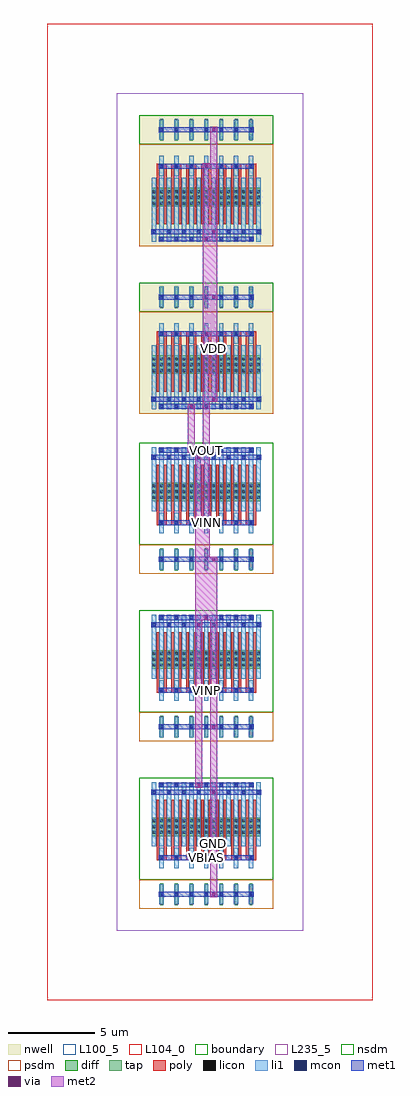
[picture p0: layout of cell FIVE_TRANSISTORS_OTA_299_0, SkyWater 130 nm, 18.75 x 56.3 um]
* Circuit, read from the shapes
.subckt FIVE_TRANSISTORS_OTA_299_0 GND VBIAS VDD VINN VINP VOUT
XM1 n1 VBIAS GND GND sky130_fd_pr__nfet_01v8 w=1.05 l=0.15 m=14
XM2 n2 VINP n1 GND sky130_fd_pr__nfet_01v8 w=1.05 l=0.15 m=14
XM3 VOUT VINN n1 GND sky130_fd_pr__nfet_01v8 w=1.05 l=0.15 m=14
XM4 VOUT n2 VDD VDD sky130_fd_pr__pfet_01v8 w=1.05 l=0.15 m=14
XM5 n2 n2 VDD VDD sky130_fd_pr__pfet_01v8 w=1.05 l=0.15 m=14
.ends

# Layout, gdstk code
import gdstk
lib = gdstk.Library(unit=1e-6, precision=1e-09)
def R(c, l, rs):  # rectangles x0, y0, x1, y1
    for r in rs: c.add(gdstk.rectangle(r[:2], r[2:], *l))
def A(c, l, x, y, w, h, nx, ny, dx, dy):  # array of equal rectangles
    R(c, l, [(x+i*dx, y+j*dy, x+i*dx+w, y+j*dy+h) for i in range(nx) for j in range(ny)])
def P(c, l, *ps):  # polygons
    for p in ps: c.add(gdstk.Polygon(p, *l))
nwell = (64, 20)
diff = (65, 20)
tap = (65, 44)
poly = (66, 20)
licon = (66, 44)
li1 = (67, 20)
mcon = (67, 44)
met1 = (68, 20)
via = (68, 44)
met2 = (69, 20)
nsdm = (93, 44)
psdm = (94, 20)
L100_5 = (100, 5)
L104_0 = (104, 0)
boundary = (235, 4)
L235_5 = (235, 5)

dcl_pmos_s_35191781_x7_y = lib.new_cell('DCL_PMOS_S_35191781_X7_Y1_1746762818')
R(dcl_pmos_s_35191781_x7_y, nwell, [(1.29,0.84,9.03,8.4)])
R(dcl_pmos_s_35191781_x7_y, diff, [(2.025,3.15,8.295,4.2)])
A(dcl_pmos_s_35191781_x7_y, tap, 2.495, 6.915, 0.17, 1.29, 7, 1, 0.86, 0)
A(dcl_pmos_s_35191781_x7_y, poly, 2.29, 2.1, 0.15, 3.36, 14, 1, 0.43, 0)
A(dcl_pmos_s_35191781_x7_y, poly, 2.29, 5.325, 0.58, 0.27, 7, 1, 0.86, 0)
A(dcl_pmos_s_35191781_x7_y, licon, 2.065, 3.23, 0.17, 0.17, 3, 3, 0.43, 0.34)
A(dcl_pmos_s_35191781_x7_y, licon, 2.925, 3.23, 0.17, 0.17, 3, 3, 0.43, 0.34)
A(dcl_pmos_s_35191781_x7_y, licon, 3.785, 3.23, 0.17, 0.17, 3, 3, 0.43, 0.34)
A(dcl_pmos_s_35191781_x7_y, licon, 4.645, 3.23, 0.17, 0.17, 3, 3, 0.43, 0.34)
A(dcl_pmos_s_35191781_x7_y, licon, 5.505, 3.23, 0.17, 0.17, 3, 3, 0.43, 0.34)
A(dcl_pmos_s_35191781_x7_y, licon, 6.365, 3.23, 0.17, 0.17, 3, 3, 0.43, 0.34)
A(dcl_pmos_s_35191781_x7_y, licon, 7.225, 3.23, 0.17, 0.17, 3, 3, 0.43, 0.34)
A(dcl_pmos_s_35191781_x7_y, licon, 2.495, 5.375, 0.17, 0.17, 7, 2, 0.86, 2.1)
A(dcl_pmos_s_35191781_x7_y, li1, 2.025, 1.09, 0.25, 3.7, 15, 1, 0.43, 0)
A(dcl_pmos_s_35191781_x7_y, li1, 2.455, 4.87, 0.25, 1.18, 7, 2, 0.86, 2.1)
A(dcl_pmos_s_35191781_x7_y, mcon, 2.495, 1.175, 0.17, 0.17, 7, 2, 0.86, 4.2)
A(dcl_pmos_s_35191781_x7_y, mcon, 2.065, 1.595, 0.17, 0.17, 8, 1, 0.86, 0)
A(dcl_pmos_s_35191781_x7_y, mcon, 2.495, 7.475, 0.17, 0.17, 7, 1, 0.86, 0)
R(dcl_pmos_s_35191781_x7_y, met1, [(2.41,1.12,7.91,1.4), (1.98,1.54,8.34,1.82), (2.41,5.32,7.91,5.6), (2.41,7.42,7.91,7.7)])
R(dcl_pmos_s_35191781_x7_y, via, [(5.085,1.185,5.235,1.335), (5.515,1.605,5.665,1.755), (5.085,5.385,5.235,5.535), (5.515,7.485,5.665,7.635)])
R(dcl_pmos_s_35191781_x7_y, met2, [(4.96,1.1,5.36,5.62), (5.39,1.52,5.79,7.72)])
R(dcl_pmos_s_35191781_x7_y, nsdm, [(1.29,6.72,9.03,8.4)])
R(dcl_pmos_s_35191781_x7_y, psdm, [(1.29,0.84,9.03,6.72)])
R(dcl_pmos_s_35191781_x7_y, L100_5, [(0,0,10.75,9.66)])
R(dcl_pmos_s_35191781_x7_y, boundary, [(0,0,10.75,9.66)])

nmos_s_30358784_x7_y1_17 = lib.new_cell('NMOS_S_30358784_X7_Y1_1746762821')
R(nmos_s_30358784_x7_y1_17, diff, [(2.025,3.15,8.295,4.2)])
A(nmos_s_30358784_x7_y1_17, tap, 2.495, 6.915, 0.17, 1.29, 7, 1, 0.86, 0)
A(nmos_s_30358784_x7_y1_17, poly, 2.29, 2.1, 0.15, 3.36, 14, 1, 0.43, 0)
A(nmos_s_30358784_x7_y1_17, poly, 2.29, 5.325, 0.58, 0.27, 7, 1, 0.86, 0)
A(nmos_s_30358784_x7_y1_17, licon, 2.065, 3.23, 0.17, 0.17, 3, 3, 0.43, 0.34)
A(nmos_s_30358784_x7_y1_17, licon, 2.925, 3.23, 0.17, 0.17, 3, 3, 0.43, 0.34)
A(nmos_s_30358784_x7_y1_17, licon, 3.785, 3.23, 0.17, 0.17, 3, 3, 0.43, 0.34)
A(nmos_s_30358784_x7_y1_17, licon, 4.645, 3.23, 0.17, 0.17, 3, 3, 0.43, 0.34)
A(nmos_s_30358784_x7_y1_17, licon, 5.505, 3.23, 0.17, 0.17, 3, 3, 0.43, 0.34)
A(nmos_s_30358784_x7_y1_17, licon, 6.365, 3.23, 0.17, 0.17, 3, 3, 0.43, 0.34)
A(nmos_s_30358784_x7_y1_17, licon, 7.225, 3.23, 0.17, 0.17, 3, 3, 0.43, 0.34)
A(nmos_s_30358784_x7_y1_17, licon, 2.495, 5.375, 0.17, 0.17, 7, 2, 0.86, 2.1)
A(nmos_s_30358784_x7_y1_17, li1, 2.025, 1.09, 0.25, 3.7, 15, 1, 0.43, 0)
A(nmos_s_30358784_x7_y1_17, li1, 2.455, 4.87, 0.25, 1.18, 7, 2, 0.86, 2.1)
A(nmos_s_30358784_x7_y1_17, mcon, 2.495, 1.175, 0.17, 0.17, 7, 2, 0.86, 4.2)
A(nmos_s_30358784_x7_y1_17, mcon, 2.065, 1.595, 0.17, 0.17, 8, 1, 0.86, 0)
A(nmos_s_30358784_x7_y1_17, mcon, 2.495, 7.475, 0.17, 0.17, 7, 1, 0.86, 0)
R(nmos_s_30358784_x7_y1_17, met1, [(2.41,1.12,7.91,1.4), (1.98,1.54,8.34,1.82), (2.41,5.32,7.91,5.6), (2.41,7.42,7.91,7.7)])
R(nmos_s_30358784_x7_y1_17, via, [(5.515,1.605,5.665,1.755), (5.515,7.485,5.665,7.635)])
R(nmos_s_30358784_x7_y1_17, met2, [(5.39,1.52,5.79,7.72)])
R(nmos_s_30358784_x7_y1_17, nsdm, [(1.29,0.84,9.03,6.72)])
R(nmos_s_30358784_x7_y1_17, psdm, [(1.29,6.72,9.03,8.4)])
R(nmos_s_30358784_x7_y1_17, L100_5, [(0,0,10.75,9.66)])
R(nmos_s_30358784_x7_y1_17, boundary, [(0,0,10.75,9.66)])

pmos_s_25226034_x7_y1_17 = lib.new_cell('PMOS_S_25226034_X7_Y1_1746762822')
R(pmos_s_25226034_x7_y1_17, nwell, [(1.29,0.84,9.03,8.4)])
R(pmos_s_25226034_x7_y1_17, diff, [(2.025,3.15,8.295,4.2)])
A(pmos_s_25226034_x7_y1_17, tap, 2.495, 6.915, 0.17, 1.29, 7, 1, 0.86, 0)
A(pmos_s_25226034_x7_y1_17, poly, 2.29, 2.1, 0.15, 3.36, 14, 1, 0.43, 0)
A(pmos_s_25226034_x7_y1_17, poly, 2.29, 5.325, 0.58, 0.27, 7, 1, 0.86, 0)
A(pmos_s_25226034_x7_y1_17, licon, 2.065, 3.23, 0.17, 0.17, 3, 3, 0.43, 0.34)
A(pmos_s_25226034_x7_y1_17, licon, 2.925, 3.23, 0.17, 0.17, 3, 3, 0.43, 0.34)
A(pmos_s_25226034_x7_y1_17, licon, 3.785, 3.23, 0.17, 0.17, 3, 3, 0.43, 0.34)
A(pmos_s_25226034_x7_y1_17, licon, 4.645, 3.23, 0.17, 0.17, 3, 3, 0.43, 0.34)
A(pmos_s_25226034_x7_y1_17, licon, 5.505, 3.23, 0.17, 0.17, 3, 3, 0.43, 0.34)
A(pmos_s_25226034_x7_y1_17, licon, 6.365, 3.23, 0.17, 0.17, 3, 3, 0.43, 0.34)
A(pmos_s_25226034_x7_y1_17, licon, 7.225, 3.23, 0.17, 0.17, 3, 3, 0.43, 0.34)
A(pmos_s_25226034_x7_y1_17, licon, 2.495, 5.375, 0.17, 0.17, 7, 2, 0.86, 2.1)
A(pmos_s_25226034_x7_y1_17, li1, 2.025, 1.09, 0.25, 3.7, 15, 1, 0.43, 0)
A(pmos_s_25226034_x7_y1_17, li1, 2.455, 4.87, 0.25, 1.18, 7, 2, 0.86, 2.1)
A(pmos_s_25226034_x7_y1_17, mcon, 2.495, 1.175, 0.17, 0.17, 7, 2, 0.86, 4.2)
A(pmos_s_25226034_x7_y1_17, mcon, 2.065, 1.595, 0.17, 0.17, 8, 1, 0.86, 0)
A(pmos_s_25226034_x7_y1_17, mcon, 2.495, 7.475, 0.17, 0.17, 7, 1, 0.86, 0)
R(pmos_s_25226034_x7_y1_17, met1, [(2.41,1.12,7.91,1.4), (1.98,1.54,8.34,1.82), (2.41,5.32,7.91,5.6), (2.41,7.42,7.91,7.7)])
R(pmos_s_25226034_x7_y1_17, via, [(5.515,1.605,5.665,1.755), (5.515,7.485,5.665,7.635)])
R(pmos_s_25226034_x7_y1_17, met2, [(5.39,1.52,5.79,7.72)])
R(pmos_s_25226034_x7_y1_17, nsdm, [(1.29,6.72,9.03,8.4)])
R(pmos_s_25226034_x7_y1_17, psdm, [(1.29,0.84,9.03,6.72)])
R(pmos_s_25226034_x7_y1_17, L100_5, [(0,0,10.75,9.66)])
R(pmos_s_25226034_x7_y1_17, boundary, [(0,0,10.75,9.66)])

nmos_4t_51745689_x7_y1_1 = lib.new_cell('NMOS_4T_51745689_X7_Y1_1746762819')
R(nmos_4t_51745689_x7_y1_1, diff, [(2.025,3.15,8.295,4.2)])
A(nmos_4t_51745689_x7_y1_1, tap, 2.495, 6.915, 0.17, 1.29, 7, 1, 0.86, 0)
A(nmos_4t_51745689_x7_y1_1, poly, 2.29, 2.1, 0.15, 3.36, 14, 1, 0.43, 0)
A(nmos_4t_51745689_x7_y1_1, poly, 2.29, 5.325, 0.58, 0.27, 7, 1, 0.86, 0)
A(nmos_4t_51745689_x7_y1_1, licon, 2.065, 3.23, 0.17, 0.17, 3, 3, 0.43, 0.34)
A(nmos_4t_51745689_x7_y1_1, licon, 2.925, 3.23, 0.17, 0.17, 3, 3, 0.43, 0.34)
A(nmos_4t_51745689_x7_y1_1, licon, 3.785, 3.23, 0.17, 0.17, 3, 3, 0.43, 0.34)
A(nmos_4t_51745689_x7_y1_1, licon, 4.645, 3.23, 0.17, 0.17, 3, 3, 0.43, 0.34)
A(nmos_4t_51745689_x7_y1_1, licon, 5.505, 3.23, 0.17, 0.17, 3, 3, 0.43, 0.34)
A(nmos_4t_51745689_x7_y1_1, licon, 6.365, 3.23, 0.17, 0.17, 3, 3, 0.43, 0.34)
A(nmos_4t_51745689_x7_y1_1, licon, 7.225, 3.23, 0.17, 0.17, 3, 3, 0.43, 0.34)
A(nmos_4t_51745689_x7_y1_1, licon, 2.495, 5.375, 0.17, 0.17, 7, 2, 0.86, 2.1)
A(nmos_4t_51745689_x7_y1_1, li1, 2.025, 1.09, 0.25, 3.7, 15, 1, 0.43, 0)
A(nmos_4t_51745689_x7_y1_1, li1, 2.455, 4.87, 0.25, 1.18, 7, 2, 0.86, 2.1)
A(nmos_4t_51745689_x7_y1_1, mcon, 2.495, 1.175, 0.17, 0.17, 7, 2, 0.86, 4.2)
A(nmos_4t_51745689_x7_y1_1, mcon, 2.065, 1.595, 0.17, 0.17, 8, 1, 0.86, 0)
A(nmos_4t_51745689_x7_y1_1, mcon, 2.495, 7.475, 0.17, 0.17, 7, 1, 0.86, 0)
R(nmos_4t_51745689_x7_y1_1, met1, [(2.41,1.12,7.91,1.4), (1.98,1.54,8.34,1.82), (2.41,5.32,7.91,5.6), (2.41,7.42,7.91,7.7)])
R(nmos_4t_51745689_x7_y1_1, nsdm, [(1.29,0.84,9.03,6.72)])
R(nmos_4t_51745689_x7_y1_1, psdm, [(1.29,6.72,9.03,8.4)])
R(nmos_4t_51745689_x7_y1_1, L100_5, [(0,0,10.75,9.66)])
R(nmos_4t_51745689_x7_y1_1, boundary, [(0,0,10.75,9.66)])

nmos_4t_82587761_x7_y1_1 = lib.new_cell('NMOS_4T_82587761_X7_Y1_1746762820')
R(nmos_4t_82587761_x7_y1_1, diff, [(2.025,3.15,8.295,4.2)])
A(nmos_4t_82587761_x7_y1_1, tap, 2.495, 6.915, 0.17, 1.29, 7, 1, 0.86, 0)
A(nmos_4t_82587761_x7_y1_1, poly, 2.29, 2.1, 0.15, 3.36, 14, 1, 0.43, 0)
A(nmos_4t_82587761_x7_y1_1, poly, 2.29, 5.325, 0.58, 0.27, 7, 1, 0.86, 0)
A(nmos_4t_82587761_x7_y1_1, licon, 2.065, 3.23, 0.17, 0.17, 3, 3, 0.43, 0.34)
A(nmos_4t_82587761_x7_y1_1, licon, 2.925, 3.23, 0.17, 0.17, 3, 3, 0.43, 0.34)
A(nmos_4t_82587761_x7_y1_1, licon, 3.785, 3.23, 0.17, 0.17, 3, 3, 0.43, 0.34)
A(nmos_4t_82587761_x7_y1_1, licon, 4.645, 3.23, 0.17, 0.17, 3, 3, 0.43, 0.34)
A(nmos_4t_82587761_x7_y1_1, licon, 5.505, 3.23, 0.17, 0.17, 3, 3, 0.43, 0.34)
A(nmos_4t_82587761_x7_y1_1, licon, 6.365, 3.23, 0.17, 0.17, 3, 3, 0.43, 0.34)
A(nmos_4t_82587761_x7_y1_1, licon, 7.225, 3.23, 0.17, 0.17, 3, 3, 0.43, 0.34)
A(nmos_4t_82587761_x7_y1_1, licon, 2.495, 5.375, 0.17, 0.17, 7, 2, 0.86, 2.1)
A(nmos_4t_82587761_x7_y1_1, li1, 2.025, 1.09, 0.25, 3.7, 15, 1, 0.43, 0)
A(nmos_4t_82587761_x7_y1_1, li1, 2.455, 4.87, 0.25, 1.18, 7, 2, 0.86, 2.1)
A(nmos_4t_82587761_x7_y1_1, mcon, 2.495, 1.175, 0.17, 0.17, 7, 2, 0.86, 4.2)
A(nmos_4t_82587761_x7_y1_1, mcon, 2.065, 1.595, 0.17, 0.17, 8, 1, 0.86, 0)
A(nmos_4t_82587761_x7_y1_1, mcon, 2.495, 7.475, 0.17, 0.17, 7, 1, 0.86, 0)
R(nmos_4t_82587761_x7_y1_1, met1, [(2.41,1.12,7.91,1.4), (1.98,1.54,8.34,1.82), (2.41,5.32,7.91,5.6), (2.41,7.42,7.91,7.7)])
R(nmos_4t_82587761_x7_y1_1, nsdm, [(1.29,0.84,9.03,6.72)])
R(nmos_4t_82587761_x7_y1_1, psdm, [(1.29,6.72,9.03,8.4)])
R(nmos_4t_82587761_x7_y1_1, L100_5, [(0,0,10.75,9.66)])
R(nmos_4t_82587761_x7_y1_1, boundary, [(0,0,10.75,9.66)])

five_transistors_ota_299 = lib.new_cell('FIVE_TRANSISTORS_OTA_299_0')
R(five_transistors_ota_299, met1, [(4.57,8.26,4.89,8.54), (4.57,8.26,4.89,8.54), (4.57,8.26,4.89,8.54), (4.57,8.26,4.89,8.54), (5.43,11.62,5.75,11.9), (5.43,11.62,5.75,11.9), (5.43,11.62,5.75,11.9), (5.43,11.62,5.75,11.9), (4.57,17.5,4.89,17.78), (4.57,17.5,4.89,17.78), (4.57,17.5,4.89,17.78), (4.57,17.5,4.89,17.78), (5,17.92,5.32,18.2), (5,17.92,5.32,18.2), (5,17.92,5.32,18.2), (5,17.92,5.32,18.2), (5.43,21.28,5.75,21.56), (5.43,21.28,5.75,21.56), (4.57,27.16,4.89,27.44), (4.57,27.16,4.89,27.44), (4.14,27.58,4.46,27.86), (4.14,27.58,4.46,27.86), (4.14,30.1,4.46,30.38), (4.14,30.1,4.46,30.38), (5,34.3,5.32,34.58), (5,34.3,5.32,34.58), (5,34.3,5.32,34.58), (5,34.3,5.32,34.58)])
P(five_transistors_ota_299, met1, [(0,0),(0,0),(0,0),(0,0)],
  [(0,0),(0,0),(0,0),(0,0)],
  [(0,0),(0,0),(0,0),(0,0)],
  [(0,0),(0,0),(0,0),(0,0)],
  [(0,0),(0,0),(0,0),(0,0)],
  [(0,0),(0,0),(0,0),(0,0)],
  [(0,0),(0,0),(0,0),(0,0)],
  [(0,0),(0,0),(0,0),(0,0)],
  [(0,0),(0,0),(0,0),(0,0)],
  [(0,0),(0,0),(0,0),(0,0)],
  [(0,0),(0,0),(0,0),(0,0)],
  [(0,0),(0,0),(0,0),(0,0)],
  [(0,0),(0,0),(0,0),(0,0)],
  [(0,0),(0,0),(0,0),(0,0)],
  [(0,0),(0,0),(0,0),(0,0)],
  [(0,0),(0,0),(0,0),(0,0)])
R(five_transistors_ota_299, via, [(4.655,8.325,4.805,8.475), (4.655,8.325,4.805,8.475), (4.655,8.325,4.805,8.475), (4.655,8.325,4.805,8.475), (5.515,11.685,5.665,11.835), (5.515,11.685,5.665,11.835), (5.515,11.685,5.665,11.835), (5.515,11.685,5.665,11.835), (4.655,17.565,4.805,17.715), (4.655,17.565,4.805,17.715), (4.655,17.565,4.805,17.715), (4.655,17.565,4.805,17.715), (5.085,17.985,5.235,18.135), (5.085,17.985,5.235,18.135), (5.085,17.985,5.235,18.135), (5.085,17.985,5.235,18.135), (5.515,21.345,5.665,21.495), (5.515,21.345,5.665,21.495), (4.655,27.225,4.805,27.375), (4.655,27.225,4.805,27.375), (4.225,27.645,4.375,27.795), (4.225,27.645,4.375,27.795), (4.225,30.165,4.375,30.315), (4.225,30.165,4.375,30.315), (5.085,34.365,5.235,34.515), (5.085,34.365,5.235,34.515), (5.085,34.365,5.235,34.515), (5.085,34.365,5.235,34.515)])
R(five_transistors_ota_299, met2, [(5.39,7.98,5.79,11.76), (4.53,8.24,4.93,8.56), (4.53,8.24,4.93,8.56), (4.53,8.24,4.93,8.56), (4.53,8.24,4.93,8.56), (4.53,8.4,4.93,17.64), (5.39,11.6,5.79,11.92), (5.39,11.6,5.79,11.92), (5.39,11.6,5.79,11.92), (5.39,11.6,5.79,11.92), (5.39,11.76,5.79,21.42), (4.53,17.48,4.93,17.8), (4.53,17.48,4.93,17.8), (4.53,17.48,4.93,17.8), (4.53,17.48,4.93,17.8), (4.53,17.64,4.93,27.3), (4.96,17.9,5.36,18.22), (4.96,17.9,5.36,18.22), (4.96,17.9,5.36,18.22), (4.96,17.9,5.36,18.22), (4.96,18.06,5.36,34.44), (5.39,21.26,5.79,21.58), (5.39,21.26,5.79,21.58), (4.53,27.14,4.93,27.46), (4.53,27.14,4.93,27.46), (4.1,27.56,4.5,27.88), (4.1,27.56,4.5,27.88), (4.1,27.72,4.5,30.24), (4.1,30.08,4.5,30.4), (4.1,30.08,4.5,30.4), (4.96,34.28,5.36,34.6), (4.96,34.28,5.36,34.6), (4.96,34.28,5.36,34.6), (4.96,34.28,5.36,34.6), (4.96,34.44,5.36,39.9), (5.39,36.54,5.79,40.32)])
P(five_transistors_ota_299, met2, [(0,0),(0,0),(0,0),(0,0)],
  [(0,0),(0,0),(0,0),(0,0)],
  [(0,0),(0,0),(0,0),(0,0)],
  [(0,0),(0,0),(0,0),(0,0)],
  [(0,0),(0,0),(0,0),(0,0)],
  [(0,0),(0,0),(0,0),(0,0)])
R(five_transistors_ota_299, L104_0, [(-4,-4,14.75,52.3)])
R(five_transistors_ota_299, L235_5, [(0,0,10.75,48.3)])
five_transistors_ota_299.add(gdstk.Reference(dcl_pmos_s_35191781_x7_y, (0,38.64)))
five_transistors_ota_299.add(gdstk.Reference(nmos_s_30358784_x7_y1_17, (0,9.66), x_reflection=True))
five_transistors_ota_299.add(gdstk.Reference(pmos_s_25226034_x7_y1_17, (0,28.98)))
five_transistors_ota_299.add(gdstk.Reference(nmos_4t_51745689_x7_y1_1, (0,28.98), x_reflection=True))
five_transistors_ota_299.add(gdstk.Reference(nmos_4t_82587761_x7_y1_1, (0,19.32), x_reflection=True))
five_transistors_ota_299.add(gdstk.Label('VDD', (5.59,33.6), layer=69, texttype=5))
five_transistors_ota_299.add(gdstk.Label('VBIAS', (5.16,4.2), layer=68, texttype=5))
five_transistors_ota_299.add(gdstk.Label('GND', (5.59,5.04), layer=69, texttype=5))
five_transistors_ota_299.add(gdstk.Label('VOUT', (5.16,27.72), layer=68, texttype=5))
five_transistors_ota_299.add(gdstk.Label('VINN', (5.16,23.52), layer=68, texttype=5))
five_transistors_ota_299.add(gdstk.Label('VINP', (5.16,13.86), layer=68, texttype=5))

lib.write_gds('FIVE_TRANSISTORS_OTA_299_0.gds')
